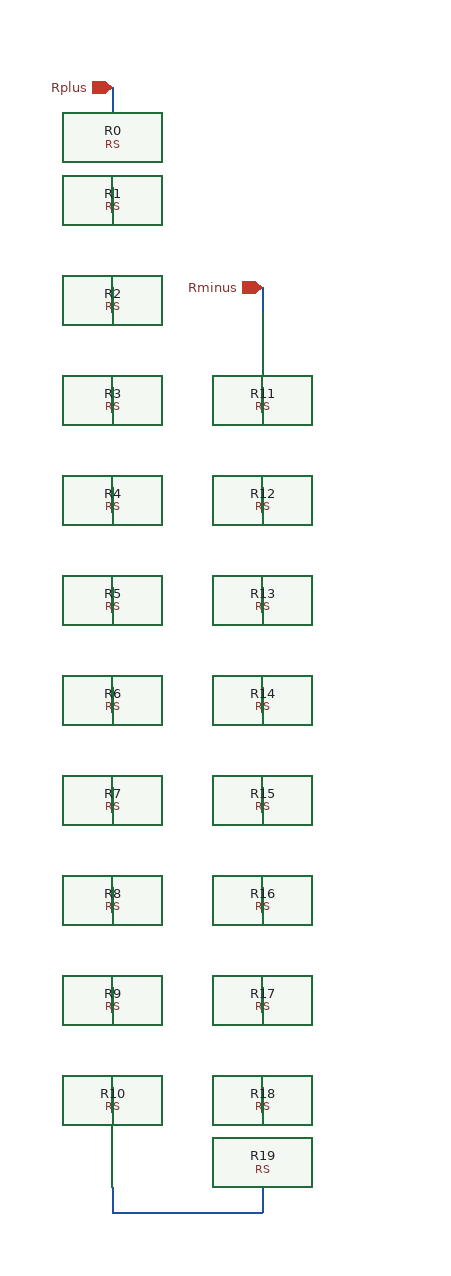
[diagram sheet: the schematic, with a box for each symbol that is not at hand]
v {xschem version=3.4.8RC file_version=1.2}
G {}
K {}
V {}
S {}
E {}
N 100 -380 100 -360 {lab=Rplus}
N 100 -300 100 -280 {lab=#net1}
N 100 -220 100 -200 {lab=#net2}
N 100 -140 100 -120 {lab=#net3}
N 100 -60 100 -40 {lab=#net4}
N 100 20 100 40 {lab=#net5}
N 100 100 100 120 {lab=#net6}
N 100 180 100 200 {lab=#net7}
N 100 260 100 280 {lab=#net8}
N 100 340 100 360 {lab=#net9}
N 100 420 100 440 {lab=#net10}
N 100 500 100 520 {lab=#net11}
N 220 -140 220 -120 {lab=#net12}
N 220 -60 220 -40 {lab=#net13}
N 220 20 220 40 {lab=#net14}
N 220 100 220 120 {lab=#net15}
N 220 180 220 200 {lab=#net16}
N 220 260 220 280 {lab=#net17}
N 220 340 220 360 {lab=#net18}
N 220 420 220 440 {lab=#net19}
N 220 500 220 520 {lab=#net20}
N 100 520 220 520 {lab=#net11}
N 220 -220 220 -200 {lab=Rminus}
C {IP62LIB/RS.sym} 100 -360 0 0 {name=R0
w=4e-6
R=1
l=100e-6
model=F_RS
spiceprefix=X
tc1=0
tc2=0}
C {devices/iopin.sym} 100 -380 0 0 {name=p1 lab=Rplus}
C {devices/iopin.sym} 220 -220 0 0 {name=p2 lab=Rminus
w=4e-6
l=100e-6}
C {IP62LIB/RS.sym} 100 -280 0 0 {name=R1
w=4e-6
R=1
l=100e-6
model=F_RS
spiceprefix=X
tc1=0
tc2=0}
C {IP62LIB/RS.sym} 100 -200 0 0 {name=R2
w=4e-6
R=1
l=100e-6
model=F_RS
spiceprefix=X
tc1=0
tc2=0}
C {IP62LIB/RS.sym} 100 -120 0 0 {name=R3
w=4e-6
R=1
l=100e-6
model=F_RS
spiceprefix=X
tc1=0
tc2=0}
C {IP62LIB/RS.sym} 100 -40 0 0 {name=R4
w=4e-6
R=1
l=100e-6
model=F_RS
spiceprefix=X
tc1=0
tc2=0}
C {IP62LIB/RS.sym} 100 40 0 0 {name=R5
w=4e-6
R=1
l=100e-6
model=F_RS
spiceprefix=X
tc1=0
tc2=0}
C {IP62LIB/RS.sym} 100 120 0 0 {name=R6
w=4e-6
R=1
l=100e-6
model=F_RS
spiceprefix=X
tc1=0
tc2=0}
C {IP62LIB/RS.sym} 100 200 0 0 {name=R7
w=4e-6
R=1
l=100e-6
model=F_RS
spiceprefix=X
tc1=0
tc2=0}
C {IP62LIB/RS.sym} 100 280 0 0 {name=R8
w=4e-6
R=1
l=100e-6
model=F_RS
spiceprefix=X
tc1=0
tc2=0}
C {IP62LIB/RS.sym} 100 360 0 0 {name=R9
w=4e-6
R=1
l=100e-6
model=F_RS
spiceprefix=X
tc1=0
tc2=0}
C {IP62LIB/RS.sym} 100 440 0 0 {name=R10
w=4e-6
R=1
l=100e-6
model=F_RS
spiceprefix=X
tc1=0
tc2=0}
C {IP62LIB/RS.sym} 220 -140 2 0 {name=R11
w=4e-6
R=1
l=100e-6
model=F_RS
spiceprefix=X
tc1=0
tc2=0}
C {IP62LIB/RS.sym} 220 -60 2 0 {name=R12
w=4e-6
R=1
l=100e-6
model=F_RS
spiceprefix=X
tc1=0
tc2=0}
C {IP62LIB/RS.sym} 220 20 2 0 {name=R13
w=4e-6
R=1
l=100e-6
model=F_RS
spiceprefix=X
tc1=0
tc2=0}
C {IP62LIB/RS.sym} 220 100 2 0 {name=R14
w=4e-6
R=1
l=100e-6
model=F_RS
spiceprefix=X
tc1=0
tc2=0}
C {IP62LIB/RS.sym} 220 180 2 0 {name=R15
w=4e-6
R=1
l=100e-6
model=F_RS
spiceprefix=X
tc1=0
tc2=0}
C {IP62LIB/RS.sym} 220 260 2 0 {name=R16
w=4e-6
R=1
l=100e-6
model=F_RS
spiceprefix=X
tc1=0
tc2=0}
C {IP62LIB/RS.sym} 220 340 2 0 {name=R17
w=4e-6
R=1
l=100e-6
model=F_RS
spiceprefix=X
tc1=0
tc2=0}
C {IP62LIB/RS.sym} 220 420 2 0 {name=R18
w=4e-6
R=1
l=100e-6
model=F_RS
spiceprefix=X
tc1=0
tc2=0}
C {IP62LIB/RS.sym} 220 500 2 0 {name=R19
w=4e-6
R=1
l=100e-6
model=F_RS
spiceprefix=X
tc1=0
tc2=0}
